VERSION 5.8 ;
NAMESCASESENSITIVE ON ;
DIVIDERCHAR "/" ;
BUSBITCHARS "[]" ;
UNITS
  DATABASE MICRONS 1000 ;
END UNITS
MANUFACTURINGGRID 0.001 ;

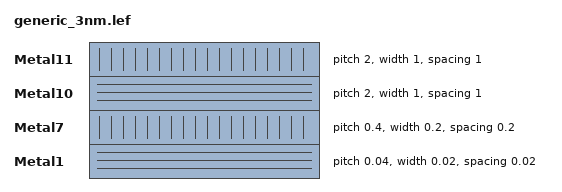
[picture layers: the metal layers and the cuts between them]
LAYER Metal1
  TYPE ROUTING ;
  DIRECTION HORIZONTAL ;
  PITCH 0.04 ;
  WIDTH 0.02 ;
  SPACING 0.02 ;
END Metal1

LAYER Metal7
  TYPE ROUTING ;
  DIRECTION VERTICAL ;
  PITCH 0.4 ;
  WIDTH 0.2 ;
  SPACING 0.2 ;
END Metal7

LAYER Metal10
  TYPE ROUTING ;
  DIRECTION HORIZONTAL ;
  PITCH 2.0 ;
  WIDTH 1.0 ;
  SPACING 1.0 ;
END Metal10

LAYER Metal11
  TYPE ROUTING ;
  DIRECTION VERTICAL ;
  PITCH 2.0 ;
  WIDTH 1.0 ;
  SPACING 1.0 ;
END Metal11

VIA Via10_11
  LAYER Metal10 ; RECT -0.5 -0.5 0.5 0.5 ;
  LAYER Via10 ; RECT -0.2 -0.2 0.2 0.2 ;
  LAYER Metal11 ; RECT -0.5 -0.5 0.5 0.5 ;
END Via10_11

END LIBRARY
